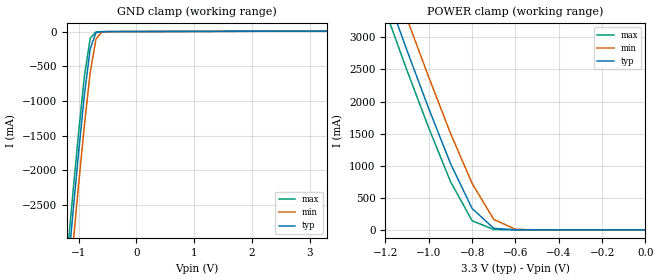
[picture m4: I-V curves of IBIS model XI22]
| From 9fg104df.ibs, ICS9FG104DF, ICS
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|   Model XI22
[Model]   XI22
Model_type   Input
Polarity   Non-Inverting
Enable   Active-High
Vinl =   0.80V
Vinh =   2.00V
C_comp   5.50pF   5.00pF   6.00pF
[Temperature Range]   27.00   70.00   0.000
[Voltage Range]   3.30V   3.00V   3.70V
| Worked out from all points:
|   GND clamp passes 1 mA (typ) near -0.46 V on its own axis
[GND_clamp]
| voltage   I(typ)   I(min)   I(max)
-3.3V     -24.05A    -24.49A    -23.79A
-1.2V     -3.55A     -4.02A     -3.26A
-1.1V     -2.63A     -3.1A      -2.34A
-1V       -1.74A     -2.2A      -1.45A
-900mV    -910mA     -1.35A     -640mA
-800mV    -250mA     -590mA     -98.01mA
-700mV    -15.97mA   -110mA     -5.31mA
-600mV    -2.13mA    -7.05mA    -1.7mA
-500mV    -1.13mA    -1.39mA    -1.09mA
3.3V      6.89mA     6.89mA     6.89mA
[POWER_clamp]
| voltage   I(typ)   I(min)   I(max)
-3.3V     24.23A     24.69A     23.95A
-1.2V     3.72A      4.21A      3.41A
-1.1V     2.79A      3.28A      2.48A
-1V       1.89A      2.38A      1.59A
-900mV    1.04A      1.51A      760mA
-800mV    340mA      730mA      150mA
-700mV    31.45mA    170mA      13.05mA
-600mV    8.7mA      16.93mA    9.04mA
0V        6.89mA     6.26mA     7.72mA
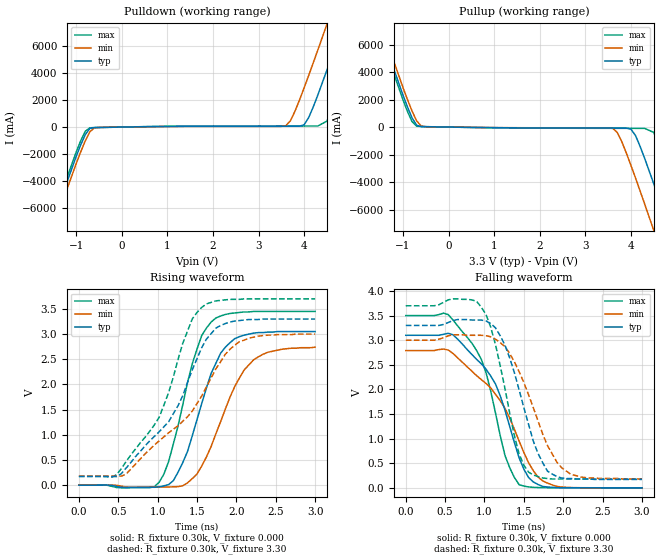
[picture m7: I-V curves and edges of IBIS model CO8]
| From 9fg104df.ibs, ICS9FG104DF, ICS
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|   Model CO8
[Model]   CO8
Model_type   Output
Polarity   Non-Inverting
Vmeas = 1.5V
C_comp   5.50pF   5.00pF   6.00pF
[Temperature Range]   27.00   70.00   0.000
[Voltage Range]   3.30V   3.00V   3.70V
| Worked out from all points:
|   slope of the pulldown table from 0 to 0.495 V, typ, clamps not added: 18 ohm
|   slope of the pullup table from 0 to 0.495 V, typ, clamps not added: 20.5 ohm
|   rising waveform, R_fixture 0.30k, V_fixture 0.000: 20-80 % time 382ps typ, 447ps min, 336ps max; typ from 0 V to 3.05 V
|   rising waveform, R_fixture 0.30k, V_fixture 3.30: 20-80 % time 695ps typ, 871ps min, 560ps max; typ from 0.17 V to 3.3 V
|   falling waveform, R_fixture 0.30k, V_fixture 0.000: 20-80 % time 456ps typ, 610ps min, 358ps max; typ from 3.1 V to 0 V
|   falling waveform, R_fixture 0.30k, V_fixture 3.30: 20-80 % time 345ps typ, 424ps min, 283ps max; typ from 3.3 V to 0.17 V
[Pulldown]
| voltage   I(typ)   I(min)   I(max)
-3.3V     -24.56A    -25.23A    -24.25A
-1.7V     -8.83A     -9.36A     -8.5A
-1.5V     -6.89A     -7.42A     -6.56A
-900mV    -1.32A     -1.84A     -1.01A
-700mV    -100mA     -350mA     -55.37mA
3.6V      62.05mA    100mA      76.49mA
4V        170mA      2.91A      76.73mA
4.3V      2.37A      5.72A      77.36mA
4.5V      4.23A      7.64A      440mA
4.9V      8.07A      11.52A     3.89A
5.3V      11.97A     15.45A     7.74A
6.6V      24.82A     28.31A     20.55A
[Pullup]
| voltage   I(typ)   I(min)   I(max)
-3.3V     24.7A      25.21A     24.38A
-1.7V     8.96A      9.5A       8.62A
-1.5V     7.02A      7.57A      6.68A
-900mV    1.44A      1.97A      1.11A
-700mV    130mA      440mA      61.07mA
3.6V      -71.56mA   -89.96mA   -90.04mA
4V        -150mA     -2.79A     -91.23mA
4.3V      -2.27A     -5.59A     -92.45mA
4.5V      -4.12A     -7.51A     -390mA
4.9V      -7.96A     -11.4A     -3.8A
5.3V      -11.87A    -15.33A    -7.65A
6.6V      -24.74A    -28.2A     -20.48A
[Ramp]
| variable   typ   min   max
dV/dt_r   1.22/0.42n   1.03/0.50n   1.45/0.35n
dV/dt_f   1.39/0.48n   1.18/0.63n   1.62/0.38n
R_load = 50.00
[Rising Waveform]
R_fixture = 0.30k
V_fixture = 0.000
V_fixture_min = 0.000
V_fixture_max = 0.000
| time   V(typ)   V(min)   V(max)
0s        130uV      100uV      160uV
1.02ns    -33.44mV   -36.44mV   58.26mV
1.14ns    11.52mV    -36.1mV    470mV
1.32ns    450mV      -11.39mV   1.6V
1.44ns    980mV      130mV      2.41V
1.56ns    1.62V      380mV      2.97V
1.74ns    2.42V      1.02V      3.32V
1.98ns    2.91V      1.96V      3.42V
2.22ns    3.02V      2.49V      3.45V
3ns       3.05V      2.74V      3.45V
[Rising Waveform]
R_fixture = 0.30k
V_fixture = 3.30
V_fixture_min = 3.00
V_fixture_max = 3.70
| time   V(typ)   V(min)   V(max)
0s        170mV      180mV      180mV
480ps     170mV      180mV      210mV
900ps     880mV      710mV      1.07V
1.02ns    1.06V      880mV      1.35V
1.26ns    1.58V      1.18V      2.5V
1.44ns    2.29V      1.47V      3.3V
1.56ns    2.73V      1.77V      3.53V
1.74ns    3.12V      2.31V      3.66V
2.04ns    3.27V      2.85V      3.69V
3ns       3.3V       3V         3.7V
[Falling Waveform]
R_fixture = 0.30k
V_fixture = 0.000
V_fixture_min = 0.000
V_fixture_max = 0.000
| time   V(typ)   V(min)   V(max)
0s        3.1V       2.79V      3.5V
540ps     3.14V      2.8V       3.52V
840ps     2.71V      2.37V      2.94V
1.02ns    2.41V      2.12V      2.34V
1.14ns    2.11V      1.9V       1.52V
1.26ns    1.58V      1.62V      660mV
1.44ns    610mV      950mV      64.07mV
1.62ns    120mV      350mV      10.05mV
1.86ns    10.22mV    59.72mV    2.17mV
3ns       150uV      420uV      120uV
[Falling Waveform]
R_fixture = 0.30k
V_fixture = 3.30
V_fixture_min = 3.00
V_fixture_max = 3.70
| time   V(typ)   V(min)   V(max)
0s        3.3V       3V         3.7V
660ps     3.42V      3.11V      3.84V
960ps     3.41V      3.1V       3.67V
1.08ns    3.34V      3.07V      3.26V
1.26ns    2.9V       2.87V      2.02V
1.44ns    1.99V      2.36V      690mV
1.56ns    1.29V      1.89V      320mV
1.8ns     340mV      860mV      190mV
1.98ns    200mV      410mV      180mV
3ns       170mV      180mV      180mV
